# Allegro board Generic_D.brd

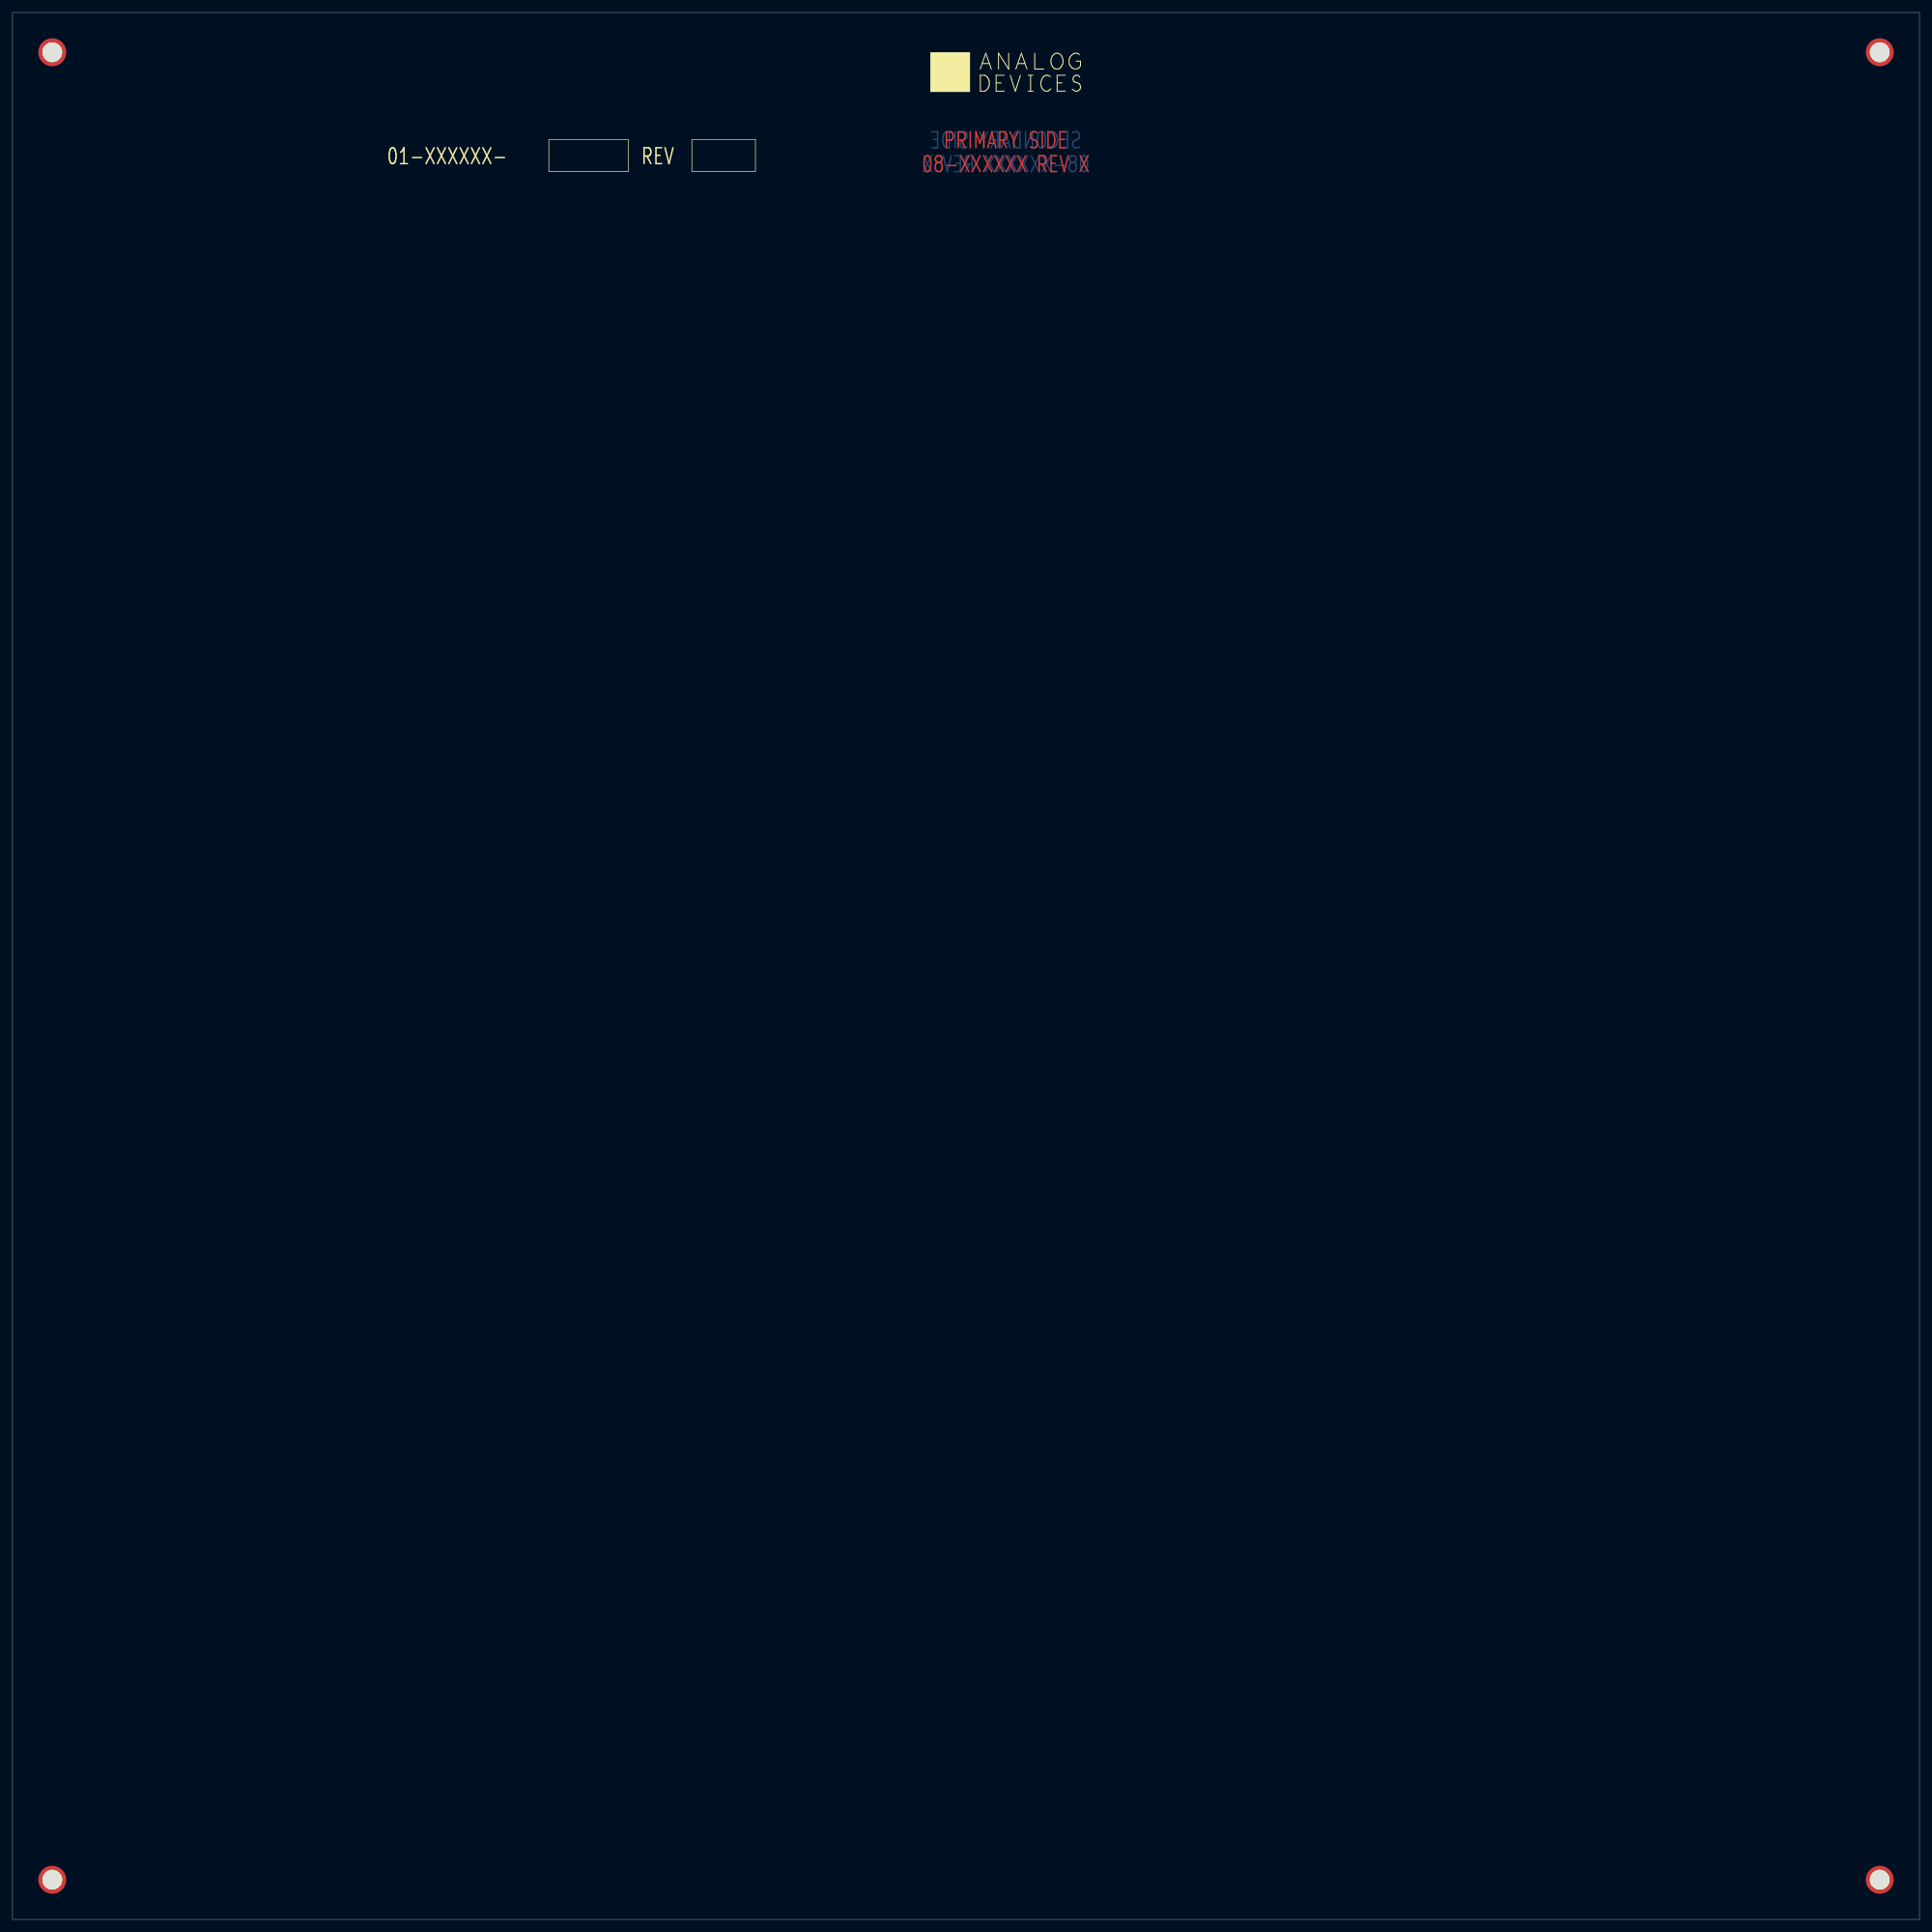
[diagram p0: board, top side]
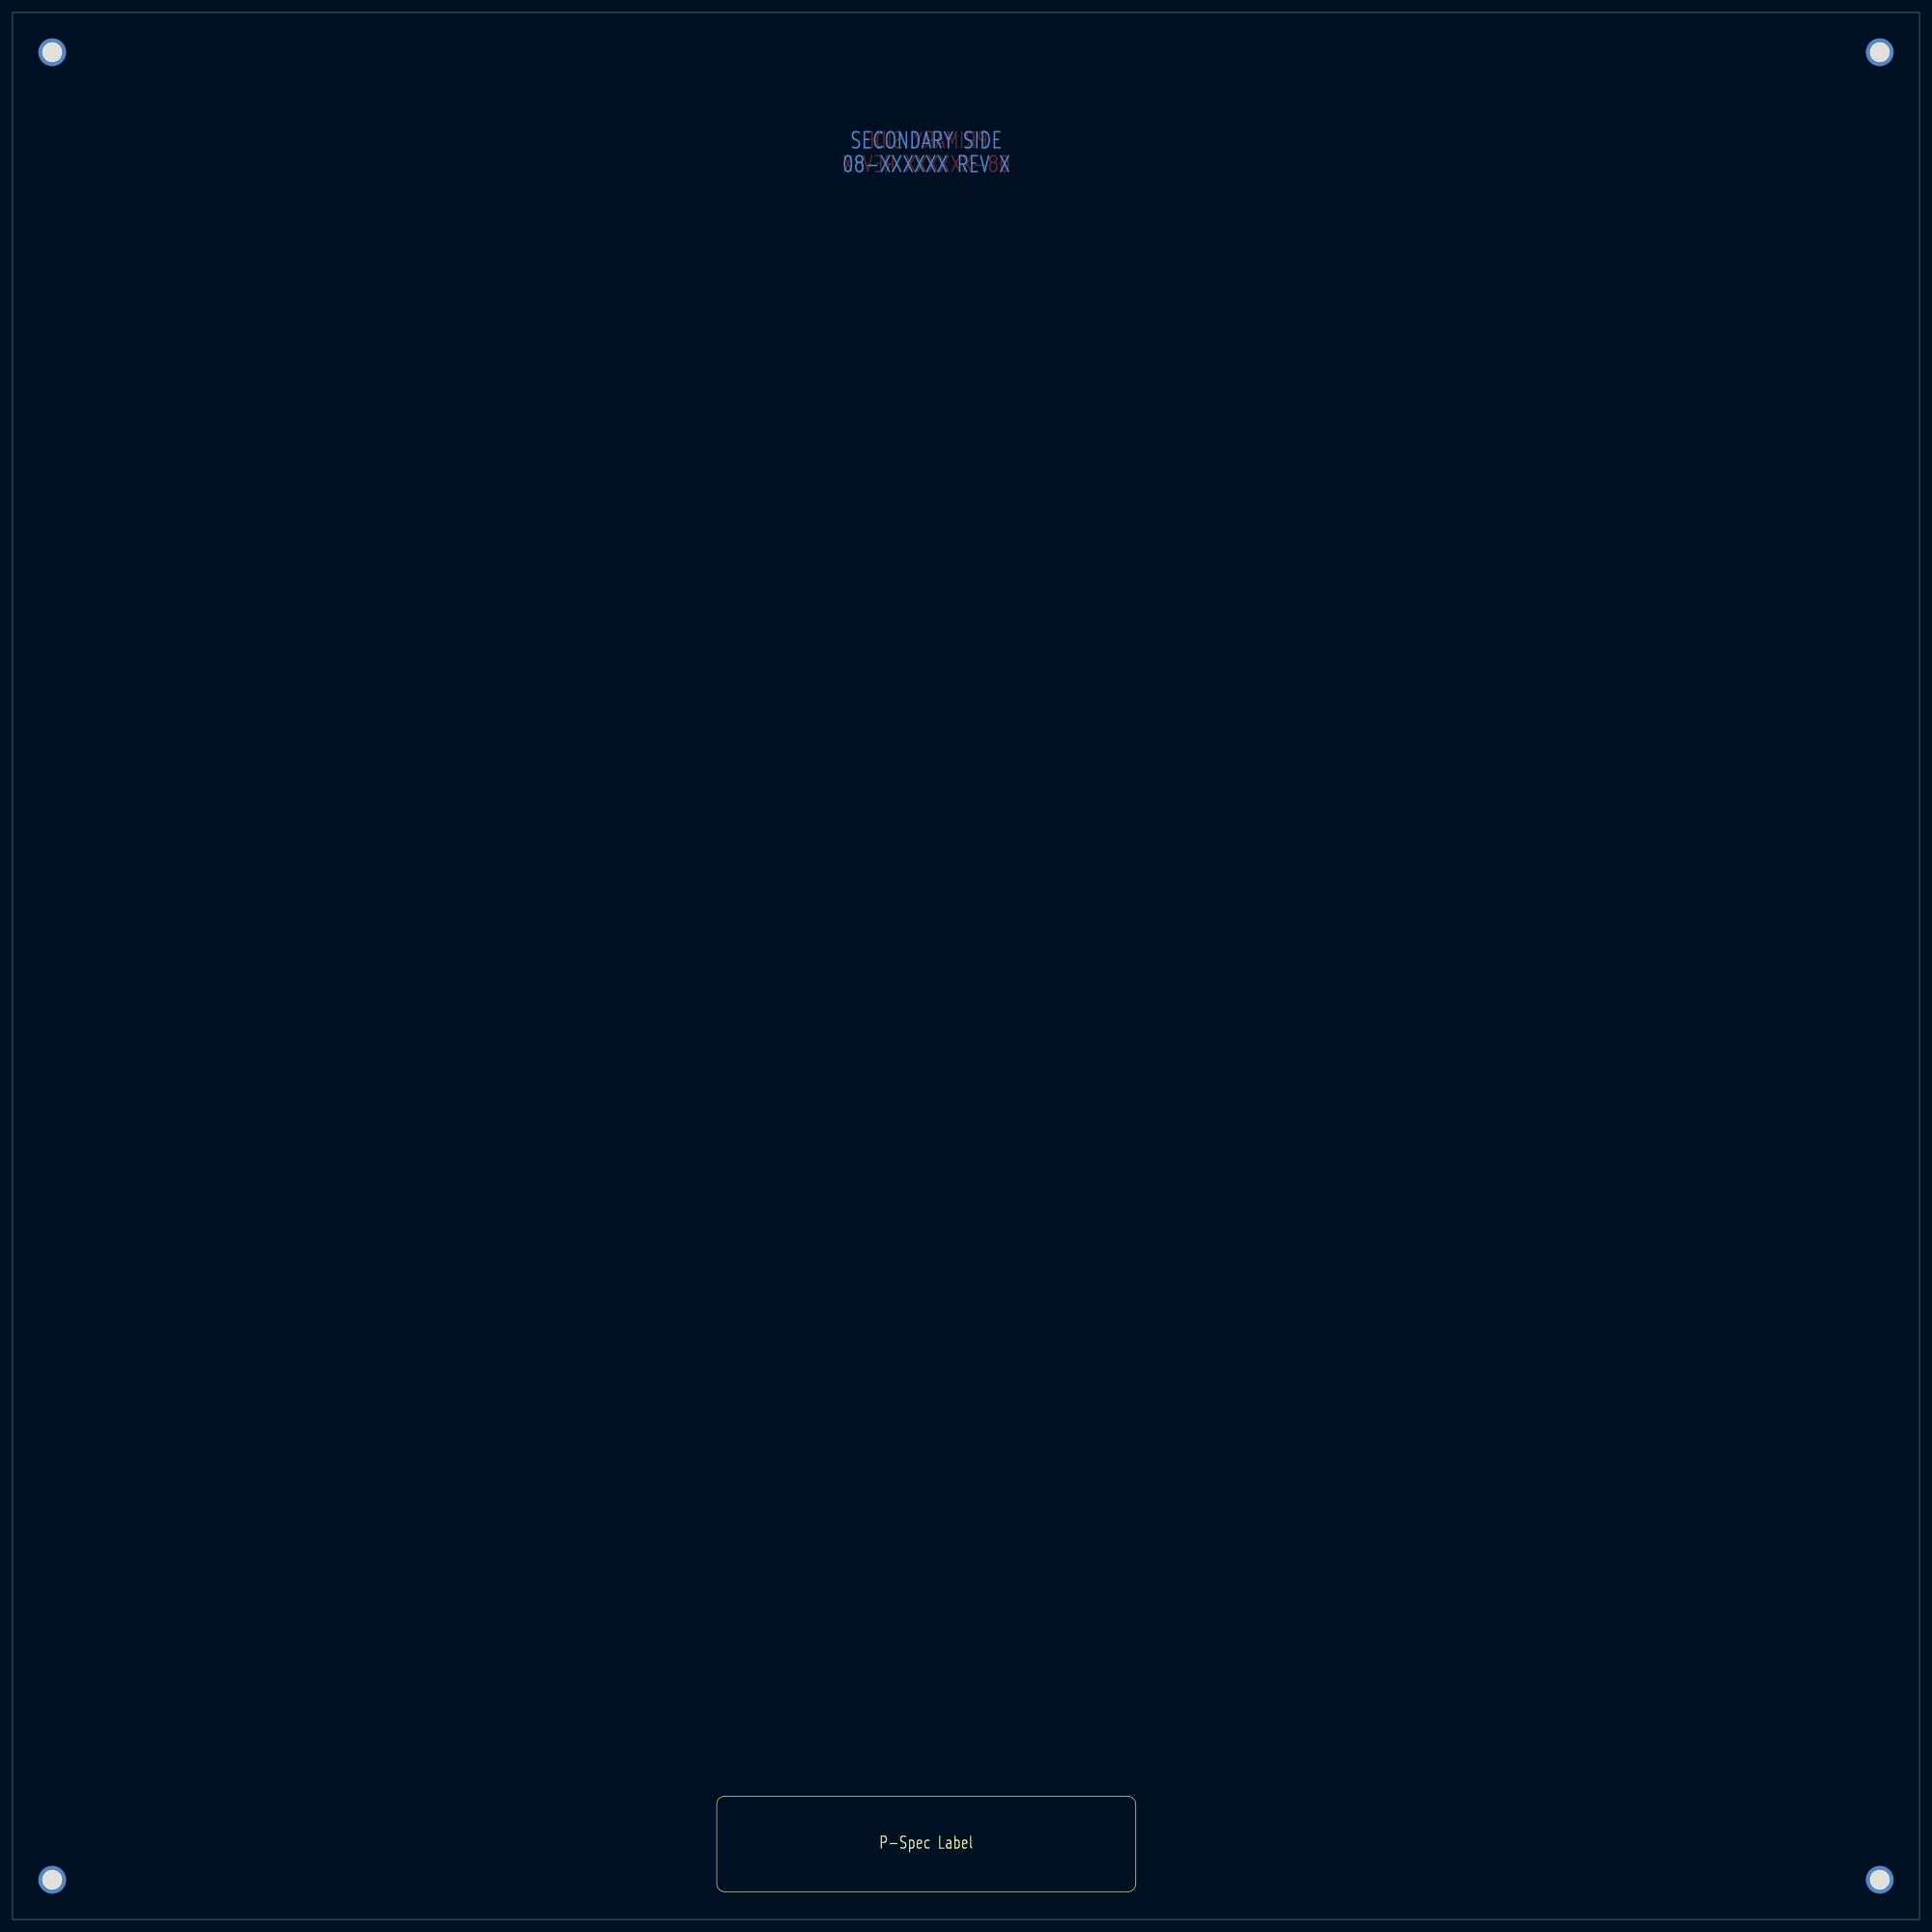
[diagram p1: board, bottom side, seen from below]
Outline 304.8 x 304.8 mm; copper layers: TOP, BOTTOM. Coordinates in mm from the lower left corner of the outline.
Outline path: 0,304.8 0,0 304.8,0 304.8,304.8 0,304.8

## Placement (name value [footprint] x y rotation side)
NOREF  -  []  304.8 304.8 180 top
NOREF#2  -  []  407.67 -3.81 0 top
NOREF#3  -  [unnamed#2]  298.45 298.45 0 top
NOREF#4  -  []  41.91 365.76 0 top
NOREF#5  -  []  0 0 0 top
NOREF#6  -  [unnamed#2]  6.35 6.35 0 top
NOREF#7  -  []  407.67 57.15 0 top
NOREF#8  -  [unnamed#2]  298.45 6.35 0 top
NOREF#9  -  []  158.75 317.5 0 top
NOREF#10  -  []  304.8 0 90 top
NOREF#11  -  []  -222.25 -146.05 0 top
NOREF#12  -  []  -222.25 -146.05 0 top
NOREF#13  -  []  177.8 304.8 0 top
NOREF#14  -  []  0 304.8 270 top
NOREF#15  -  []  158.75 279.4 270 top
NOREF#16  -  []  -38.1 304.8 0 top
NOREF#17  -  []  88.9 279.4 0 top
NOREF#18  -  []  -222.25 -146.05 0 top
NOREF#19  -  []  372.11 73.66 90 top
NOREF#20  -  [unnamed#2]  6.35 298.45 0 top
NOREF#21  -  []  146.7 292.1 180 bottom
NOREF#22  -  []  158.76 12.06 180 bottom

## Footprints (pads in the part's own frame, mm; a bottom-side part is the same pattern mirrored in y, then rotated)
unnamed#2
  round 4.445 hole 3.175 unplated: (0,0)

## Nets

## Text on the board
DIMENSION: REF | 11.750 | -.250 | "0"
User.45: FIGURE | SIZE | 125.0 | PLATED | NON-PLATED | FINISHED HOLES IN MILS | ALL UNITS ARE IN MILS | QTY | 4 | TOLERANCE/NOTES
